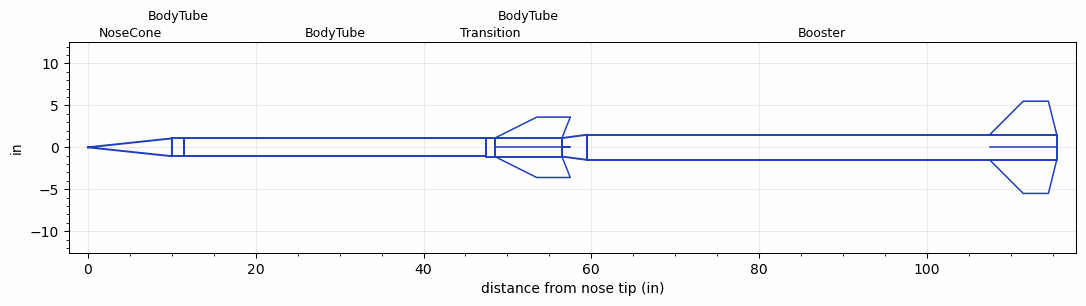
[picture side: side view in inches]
<RASAeroDocument>
 <FileVersion>2</FileVersion>
 <RocketDesign>
  <NoseCone>
   <Length>10</Length>
   <Diameter>2.125</Diameter>
   <Shape>Conical</Shape>
   <BluntRadius>0.065</BluntRadius>
   <Location>0</Location>
  </NoseCone>
  <BodyTube>
   <Length>1.5</Length>
   <Diameter>2.125</Diameter>
   <Location>10</Location>
  </BodyTube>
  <BodyTube>
   <Length>36</Length>
   <Diameter>2.125</Diameter>
   <Location>11.5</Location>
  </BodyTube>
  <Transition>
   <Length>1</Length>
   <Diameter>2.2</Diameter>
   <Location>47.5</Location>
   <RearDiameter>2.2</RearDiameter>
  </Transition>
  <BodyTube>
   <Length>8</Length>
   <Diameter>2.2</Diameter>
   <Location>48.5</Location>
   <Fin>
    <Count>4</Count>
    <Chord>8</Chord>
    <Span>2.5</Span>
    <SweepDistance>5</SweepDistance>
    <TipChord>4</TipChord>
    <Thickness>0.25</Thickness>
    <LERadius>0.02</LERadius>
    <Location>8</Location>
    <AirfoilSection>Hexagonal</AirfoilSection>
    <FX1>0.75</FX1>
    <FX3>0.75</FX3>
   </Fin>
  </BodyTube>
  <Booster>
   <Length>56</Length>
   <Diameter>3</Diameter>
   <InsideDiameter>2.2</InsideDiameter>
   <Location>56.5</Location>
   <ShoulderLength>3</ShoulderLength>
   <Fin>
    <Count>4</Count>
    <Chord>8</Chord>
    <Span>4</Span>
    <SweepDistance>4</SweepDistance>
    <TipChord>3</TipChord>
    <Thickness>0.1875</Thickness>
    <LERadius>0.02</LERadius>
    <Location>8</Location>
    <AirfoilSection>Hexagonal</AirfoilSection>
    <FX1>0.75</FX1>
    <FX3>0.75</FX3>
   </Fin>
  </Booster>
  <Surface>Rough Camouflage Paint</Surface>
  <ModifiedBarrowman>True</ModifiedBarrowman>
  <Turbulence>True</Turbulence>
  <UseBooster1>False</UseBooster1>
  <UseBooster2>False</UseBooster2>
 </RocketDesign>
 <LaunchSite>
  <Altitude>4000</Altitude>
  <Pressure>27.83</Pressure>
  <RodAngle>2</RodAngle>
  <RodLength>10</RodLength>
  <Temperature>51.87</Temperature>
  <WindSpeed>4.47</WindSpeed>
 </LaunchSite>
 <Recovery>
  <Altitude1>0</Altitude1>
  <Altitude2>0</Altitude2>
  <DeviceType1>None</DeviceType1>
  <DeviceType2>None</DeviceType2>
  <Event1>False</Event1>
  <Event2>False</Event2>
  <Size1>0</Size1>
  <Size2>0</Size2>
  <EventType1>None</EventType1>
  <EventType2>None</EventType2>
  <CD1>0</CD1>
  <CD2>0</CD2>
 </Recovery>
 <SimulationList>
  <Simulation>
   <SustainerEngine>M2091BPNC  (Polaris)</SustainerEngine>
   <SustainerLaunchWt>12</SustainerLaunchWt>
   <SustainerNozzleDiameter>1.9</SustainerNozzleDiameter>
   <SustainerCG>33.57</SustainerCG>
   <SustainerIgnitionDelay>14</SustainerIgnitionDelay>
   <Booster1Engine>N3110RBNC  (Polaris)</Booster1Engine>
   <Booster1LaunchWt>33</Booster1LaunchWt>
   <Booster1SeparationDelay>0</Booster1SeparationDelay>
   <Booster1IgnitionDelay>0</Booster1IgnitionDelay>
   <Booster1CG>69</Booster1CG>
   <Booster1NozzleDiameter>2.5</Booster1NozzleDiameter>
   <IncludeBooster1>True</IncludeBooster1>
   <Booster2Delay>0</Booster2Delay>
   <IncludeBooster2>False</IncludeBooster2>
   <TimetoApogee>147.87</TimetoApogee>
   <MaxAltitude>303914.9</MaxAltitude>
   <MaxVelocity>5573.855</MaxVelocity>
  </Simulation>
 </SimulationList>
</RASAeroDocument>
